VERSION 5.7 ;
  NOWIREEXTENSIONATPIN ON ;
  DIVIDERCHAR "/" ;
  BUSBITCHARS "[]" ;
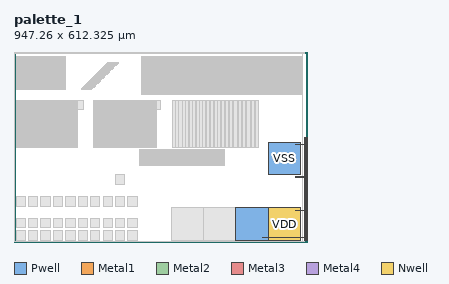
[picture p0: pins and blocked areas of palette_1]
MACRO palette_1
  CLASS BLOCK ;
  FOREIGN palette_1 ;
  ORIGIN 0.000 0.000 ;
  SIZE 947.260 BY 612.325 ;
  PIN VSS
    DIRECTION INOUT ;
    USE GROUND ;
    PORT
      LAYER Pwell ;
        RECT 819.000 218.000 923.000 322.000 ;
        RECT 715.000 6.000 819.000 110.000 ;
      LAYER Metal1 ;
        RECT 906.130 312.895 945.320 313.880 ;
        RECT 802.090 14.115 945.320 15.110 ;
      LAYER Metal2 ;
        RECT 941.425 312.895 945.425 313.885 ;
        RECT 941.425 14.120 945.430 15.110 ;
      LAYER Metal3 ;
        RECT 941.425 312.895 945.425 313.885 ;
        RECT 941.425 14.120 945.430 15.110 ;
      LAYER Metal4 ;
        RECT 941.425 6.015 945.425 336.370 ;
    END
  END VSS
  PIN VDD
    DIRECTION INOUT ;
    USE POWER ;
    PORT
      LAYER Nwell ;
        RECT 819.000 6.000 923.000 110.000 ;
      LAYER Metal1 ;
        RECT 906.135 208.865 940.095 209.850 ;
        RECT 906.375 100.730 939.890 101.710 ;
      LAYER Metal2 ;
        RECT 936.425 208.860 940.425 209.850 ;
        RECT 936.425 100.725 940.425 101.715 ;
      LAYER Metal3 ;
        RECT 936.425 208.860 940.425 209.850 ;
        RECT 936.425 100.725 940.425 101.715 ;
      LAYER Metal4 ;
        RECT 936.425 6.015 940.425 336.370 ;
    END
  END VDD
  OBS
      LAYER Pwell ;
        RECT 507.000 6.000 611.000 110.000 ;
      LAYER Nwell ;
        RECT 611.000 6.000 715.000 110.000 ;
      LAYER Metal1 ;
        RECT 287.000 116.000 317.000 146.000 ;
        RECT 327.000 116.000 357.000 146.000 ;
        RECT 367.000 116.000 397.000 146.000 ;
        RECT 327.000 46.000 357.000 76.000 ;
        RECT 367.000 46.000 397.000 76.000 ;
        RECT 327.000 6.000 357.000 36.000 ;
        RECT 367.000 6.000 397.000 36.000 ;
      LAYER Metal2 ;
        RECT 207.000 116.000 237.000 146.000 ;
        RECT 247.000 116.000 277.000 146.000 ;
        RECT 287.000 116.000 317.000 146.000 ;
        RECT 247.000 46.000 277.000 76.000 ;
        RECT 287.000 46.000 317.000 76.000 ;
        RECT 247.000 6.000 277.000 36.000 ;
        RECT 287.000 6.000 317.000 36.000 ;
      LAYER Metal3 ;
        RECT 255.420 426.000 285.420 456.000 ;
        RECT 286.420 426.000 316.420 456.000 ;
        RECT 317.420 426.000 347.420 456.000 ;
        RECT 348.420 426.000 378.420 456.000 ;
        RECT 379.420 426.000 409.420 456.000 ;
        RECT 410.420 426.000 440.420 456.000 ;
        RECT 441.420 426.000 471.420 456.000 ;
        RECT 127.000 116.000 157.000 146.000 ;
        RECT 167.000 116.000 197.000 146.000 ;
        RECT 207.000 116.000 237.000 146.000 ;
        RECT 167.000 46.000 197.000 76.000 ;
        RECT 207.000 46.000 237.000 76.000 ;
        RECT 167.000 6.000 197.000 36.000 ;
        RECT 207.000 6.000 237.000 36.000 ;
      LAYER Metal4 ;
        RECT 2.550 608.255 935.650 609.265 ;
        RECT 1.520 6.000 2.530 605.275 ;
        RECT 7.000 426.000 37.000 456.000 ;
        RECT 38.000 426.000 68.000 456.000 ;
        RECT 69.000 426.000 99.000 456.000 ;
        RECT 100.000 426.000 130.000 456.000 ;
        RECT 131.000 426.000 161.000 456.000 ;
        RECT 162.000 426.000 192.000 456.000 ;
        RECT 193.000 426.000 223.000 456.000 ;
        RECT 255.420 306.000 256.420 456.000 ;
        RECT 256.800 306.000 257.800 456.000 ;
        RECT 258.180 306.000 259.180 456.000 ;
        RECT 259.560 306.000 260.560 456.000 ;
        RECT 260.940 306.000 261.940 456.000 ;
        RECT 262.330 306.000 263.330 456.000 ;
        RECT 263.720 306.000 264.720 456.000 ;
        RECT 265.110 306.000 266.110 456.000 ;
        RECT 266.500 306.000 267.500 456.000 ;
        RECT 267.900 306.000 268.900 456.000 ;
        RECT 269.300 306.000 270.300 456.000 ;
        RECT 270.700 306.000 271.700 456.000 ;
        RECT 272.100 306.000 273.100 456.000 ;
        RECT 273.510 306.000 274.510 456.000 ;
        RECT 274.920 306.000 275.920 456.000 ;
        RECT 276.330 306.000 277.330 456.000 ;
        RECT 277.740 306.000 278.740 456.000 ;
        RECT 279.160 306.000 280.160 456.000 ;
        RECT 280.580 306.000 281.580 456.000 ;
        RECT 282.000 306.000 283.000 456.000 ;
        RECT 283.420 306.000 284.420 456.000 ;
        RECT 284.850 306.000 285.850 456.000 ;
        RECT 286.280 306.000 287.280 456.000 ;
        RECT 287.710 306.000 288.710 456.000 ;
        RECT 289.140 306.000 290.140 456.000 ;
        RECT 290.580 306.000 291.580 456.000 ;
        RECT 292.020 306.000 293.020 456.000 ;
        RECT 293.460 306.000 294.460 456.000 ;
        RECT 294.900 306.000 295.900 456.000 ;
        RECT 296.350 306.000 297.350 456.000 ;
        RECT 297.800 306.000 298.800 456.000 ;
        RECT 299.250 306.000 300.250 456.000 ;
        RECT 300.700 306.000 301.700 456.000 ;
        RECT 302.160 306.000 303.160 456.000 ;
        RECT 303.620 306.000 304.620 456.000 ;
        RECT 305.080 306.000 306.080 456.000 ;
        RECT 306.540 306.000 307.540 456.000 ;
        RECT 308.010 306.000 309.010 456.000 ;
        RECT 309.480 306.000 310.480 456.000 ;
        RECT 310.950 306.000 311.950 456.000 ;
        RECT 312.420 306.000 313.420 456.000 ;
        RECT 313.900 306.000 314.900 456.000 ;
        RECT 315.380 306.000 316.380 456.000 ;
        RECT 316.860 306.000 317.860 456.000 ;
        RECT 318.340 306.000 319.340 456.000 ;
        RECT 319.830 306.000 320.830 456.000 ;
        RECT 321.320 306.000 322.320 456.000 ;
        RECT 322.810 306.000 323.810 456.000 ;
        RECT 324.300 306.000 325.300 456.000 ;
        RECT 325.800 306.000 326.800 456.000 ;
        RECT 327.300 306.000 328.300 456.000 ;
        RECT 328.800 306.000 329.800 456.000 ;
        RECT 330.300 306.000 331.300 456.000 ;
        RECT 331.810 306.000 332.810 456.000 ;
        RECT 333.320 306.000 334.320 456.000 ;
        RECT 334.830 306.000 335.830 456.000 ;
        RECT 336.340 306.000 337.340 456.000 ;
        RECT 337.860 306.000 338.860 456.000 ;
        RECT 339.380 306.000 340.380 456.000 ;
        RECT 340.900 306.000 341.900 456.000 ;
        RECT 342.420 306.000 343.420 456.000 ;
        RECT 343.950 306.000 344.950 456.000 ;
        RECT 345.480 306.000 346.480 456.000 ;
        RECT 347.010 306.000 348.010 456.000 ;
        RECT 348.540 306.000 349.540 456.000 ;
        RECT 350.080 306.000 351.080 456.000 ;
        RECT 351.620 306.000 352.620 456.000 ;
        RECT 353.160 306.000 354.160 456.000 ;
        RECT 354.700 306.000 355.700 456.000 ;
        RECT 356.250 306.000 357.250 456.000 ;
        RECT 357.800 306.000 358.800 456.000 ;
        RECT 359.350 306.000 360.350 456.000 ;
        RECT 360.900 306.000 361.900 456.000 ;
        RECT 362.460 306.000 363.460 456.000 ;
        RECT 364.020 306.000 365.020 456.000 ;
        RECT 365.580 306.000 366.580 456.000 ;
        RECT 367.140 306.000 368.140 456.000 ;
        RECT 368.710 306.000 369.710 456.000 ;
        RECT 370.280 306.000 371.280 456.000 ;
        RECT 371.850 306.000 372.850 456.000 ;
        RECT 373.420 306.000 374.420 456.000 ;
        RECT 375.000 306.000 376.000 456.000 ;
        RECT 376.580 306.000 377.580 456.000 ;
        RECT 378.160 306.000 379.160 456.000 ;
        RECT 379.740 306.000 380.740 456.000 ;
        RECT 381.330 306.000 382.330 456.000 ;
        RECT 382.920 306.000 383.920 456.000 ;
        RECT 384.510 306.000 385.510 456.000 ;
        RECT 386.100 306.000 387.100 456.000 ;
        RECT 387.700 306.000 388.700 456.000 ;
        RECT 389.300 306.000 390.300 456.000 ;
        RECT 390.900 306.000 391.900 456.000 ;
        RECT 392.500 306.000 393.500 456.000 ;
        RECT 394.110 306.000 395.110 456.000 ;
        RECT 395.720 306.000 396.720 456.000 ;
        RECT 397.330 306.000 398.330 456.000 ;
        RECT 398.940 306.000 399.940 456.000 ;
        RECT 400.560 306.000 401.560 456.000 ;
        RECT 402.180 306.000 403.180 456.000 ;
        RECT 403.800 306.000 404.800 456.000 ;
        RECT 405.420 306.000 406.420 456.000 ;
        RECT 407.050 306.000 408.050 456.000 ;
        RECT 408.680 306.000 409.680 456.000 ;
        RECT 410.310 306.000 411.310 456.000 ;
        RECT 411.940 306.000 412.940 456.000 ;
        RECT 413.580 306.000 414.580 456.000 ;
        RECT 415.220 306.000 416.220 456.000 ;
        RECT 416.860 306.000 417.860 456.000 ;
        RECT 418.500 306.000 419.500 456.000 ;
        RECT 420.150 306.000 421.150 456.000 ;
        RECT 421.800 306.000 422.800 456.000 ;
        RECT 423.450 306.000 424.450 456.000 ;
        RECT 425.100 306.000 426.100 456.000 ;
        RECT 426.760 306.000 427.760 456.000 ;
        RECT 428.420 306.000 429.420 456.000 ;
        RECT 430.080 306.000 431.080 456.000 ;
        RECT 431.740 306.000 432.740 456.000 ;
        RECT 433.410 306.000 434.410 456.000 ;
        RECT 435.080 306.000 436.080 456.000 ;
        RECT 436.750 306.000 437.750 456.000 ;
        RECT 438.420 306.000 439.420 456.000 ;
        RECT 440.100 306.000 441.100 456.000 ;
        RECT 441.780 306.000 442.780 456.000 ;
        RECT 443.460 306.000 444.460 456.000 ;
        RECT 445.140 306.000 446.140 456.000 ;
        RECT 446.830 306.000 447.830 456.000 ;
        RECT 448.520 306.000 449.520 456.000 ;
        RECT 450.210 306.000 451.210 456.000 ;
        RECT 451.900 306.000 452.900 456.000 ;
        RECT 453.600 306.000 454.600 456.000 ;
        RECT 455.300 306.000 456.300 456.000 ;
        RECT 457.000 306.000 458.000 456.000 ;
        RECT 458.700 306.000 459.700 456.000 ;
        RECT 326.400 216.000 357.600 216.600 ;
        RECT 326.400 186.000 327.000 216.000 ;
        RECT 357.000 186.000 357.600 216.000 ;
        RECT 326.400 185.400 357.600 186.000 ;
        RECT 47.000 116.000 77.000 146.000 ;
        RECT 87.000 116.000 117.000 146.000 ;
        RECT 127.000 116.000 157.000 146.000 ;
        RECT 87.000 46.000 117.000 76.000 ;
        RECT 127.000 46.000 157.000 76.000 ;
        RECT 87.000 6.000 117.000 36.000 ;
        RECT 127.000 6.000 157.000 36.000 ;
        RECT 928.680 6.000 929.130 605.275 ;
        RECT 1.870 0.785 934.970 1.795 ;
      LAYER Metal5 ;
        RECT 2.550 608.255 935.650 609.265 ;
        RECT 1.520 6.000 2.530 605.275 ;
        RECT 9.265 596.390 166.265 597.390 ;
        RECT 9.265 594.390 166.265 595.390 ;
        RECT 9.265 592.390 166.265 593.390 ;
        RECT 9.265 590.390 166.265 591.390 ;
        RECT 9.265 588.390 166.265 589.390 ;
        RECT 9.265 586.390 166.265 587.390 ;
        RECT 9.265 584.390 166.265 585.390 ;
        RECT 9.265 582.390 166.265 583.390 ;
        RECT 9.265 580.390 166.265 581.390 ;
        RECT 9.265 578.390 166.265 579.390 ;
        RECT 303.265 578.390 305.265 579.390 ;
        RECT 302.265 577.390 304.265 578.390 ;
        RECT 307.265 578.385 309.265 579.385 ;
        RECT 9.265 576.390 166.265 577.390 ;
        RECT 301.265 576.390 303.265 577.390 ;
        RECT 306.265 577.385 308.265 578.385 ;
        RECT 311.265 578.380 313.265 579.380 ;
        RECT 315.265 578.380 317.265 579.380 ;
        RECT 319.265 578.380 321.265 579.380 ;
        RECT 323.265 578.380 325.265 579.380 ;
        RECT 327.265 578.380 329.265 579.380 ;
        RECT 331.265 578.380 333.265 579.380 ;
        RECT 335.265 578.380 337.265 579.380 ;
        RECT 300.265 575.390 302.265 576.390 ;
        RECT 305.265 576.385 307.265 577.385 ;
        RECT 310.265 577.380 312.265 578.380 ;
        RECT 314.265 577.380 316.265 578.380 ;
        RECT 318.265 577.380 320.265 578.380 ;
        RECT 322.265 577.380 324.265 578.380 ;
        RECT 326.265 577.380 328.265 578.380 ;
        RECT 330.265 577.380 332.265 578.380 ;
        RECT 334.265 577.380 336.265 578.380 ;
        RECT 9.265 574.390 166.265 575.390 ;
        RECT 299.265 574.390 301.265 575.390 ;
        RECT 304.265 575.385 306.265 576.385 ;
        RECT 309.265 576.380 311.265 577.380 ;
        RECT 313.265 576.380 315.265 577.380 ;
        RECT 317.265 576.380 319.265 577.380 ;
        RECT 321.265 576.380 323.265 577.380 ;
        RECT 325.265 576.380 327.265 577.380 ;
        RECT 329.265 576.380 331.265 577.380 ;
        RECT 333.265 576.380 335.265 577.380 ;
        RECT 298.265 573.390 300.265 574.390 ;
        RECT 303.265 574.385 305.265 575.385 ;
        RECT 308.265 575.380 310.265 576.380 ;
        RECT 312.265 575.380 314.265 576.380 ;
        RECT 316.265 575.380 318.265 576.380 ;
        RECT 320.265 575.380 322.265 576.380 ;
        RECT 324.265 575.380 326.265 576.380 ;
        RECT 328.265 575.380 330.265 576.380 ;
        RECT 332.265 575.380 334.265 576.380 ;
        RECT 9.265 572.390 166.265 573.390 ;
        RECT 297.265 572.390 299.265 573.390 ;
        RECT 302.265 573.385 304.265 574.385 ;
        RECT 307.265 574.380 309.265 575.380 ;
        RECT 311.265 574.380 313.265 575.380 ;
        RECT 315.265 574.380 317.265 575.380 ;
        RECT 319.265 574.380 321.265 575.380 ;
        RECT 323.265 574.380 325.265 575.380 ;
        RECT 327.265 574.380 329.265 575.380 ;
        RECT 331.265 574.380 333.265 575.380 ;
        RECT 296.265 571.390 298.265 572.390 ;
        RECT 301.265 572.385 303.265 573.385 ;
        RECT 306.265 573.380 308.265 574.380 ;
        RECT 310.265 573.380 312.265 574.380 ;
        RECT 314.265 573.380 316.265 574.380 ;
        RECT 318.265 573.380 320.265 574.380 ;
        RECT 322.265 573.380 324.265 574.380 ;
        RECT 326.265 573.380 328.265 574.380 ;
        RECT 330.265 573.380 332.265 574.380 ;
        RECT 9.265 570.390 166.265 571.390 ;
        RECT 295.265 570.390 297.265 571.390 ;
        RECT 300.265 571.385 302.265 572.385 ;
        RECT 305.265 572.380 307.265 573.380 ;
        RECT 309.265 572.380 311.265 573.380 ;
        RECT 313.265 572.380 315.265 573.380 ;
        RECT 317.265 572.380 319.265 573.380 ;
        RECT 321.265 572.380 323.265 573.380 ;
        RECT 325.265 572.380 327.265 573.380 ;
        RECT 329.265 572.380 331.265 573.380 ;
        RECT 294.265 569.390 296.265 570.390 ;
        RECT 299.265 570.385 301.265 571.385 ;
        RECT 304.265 571.380 306.265 572.380 ;
        RECT 308.265 571.380 310.265 572.380 ;
        RECT 312.265 571.380 314.265 572.380 ;
        RECT 316.265 571.380 318.265 572.380 ;
        RECT 320.265 571.380 322.265 572.380 ;
        RECT 324.265 571.380 326.265 572.380 ;
        RECT 328.265 571.380 330.265 572.380 ;
        RECT 9.265 568.390 166.265 569.390 ;
        RECT 293.265 568.390 295.265 569.390 ;
        RECT 298.265 569.385 300.265 570.385 ;
        RECT 303.265 570.380 305.265 571.380 ;
        RECT 307.265 570.380 309.265 571.380 ;
        RECT 311.265 570.380 313.265 571.380 ;
        RECT 315.265 570.380 317.265 571.380 ;
        RECT 319.265 570.380 321.265 571.380 ;
        RECT 323.265 570.380 325.265 571.380 ;
        RECT 327.265 570.380 329.265 571.380 ;
        RECT 292.265 567.390 294.265 568.390 ;
        RECT 297.265 568.385 299.265 569.385 ;
        RECT 302.265 569.380 304.265 570.380 ;
        RECT 306.265 569.380 308.265 570.380 ;
        RECT 310.265 569.380 312.265 570.380 ;
        RECT 314.265 569.380 316.265 570.380 ;
        RECT 318.265 569.380 320.265 570.380 ;
        RECT 322.265 569.380 324.265 570.380 ;
        RECT 326.265 569.380 328.265 570.380 ;
        RECT 9.265 566.390 166.265 567.390 ;
        RECT 291.265 566.390 293.265 567.390 ;
        RECT 296.265 567.385 298.265 568.385 ;
        RECT 301.265 568.380 303.265 569.380 ;
        RECT 305.265 568.380 307.265 569.380 ;
        RECT 309.265 568.380 311.265 569.380 ;
        RECT 313.265 568.380 315.265 569.380 ;
        RECT 317.265 568.380 319.265 569.380 ;
        RECT 321.265 568.380 323.265 569.380 ;
        RECT 325.265 568.380 327.265 569.380 ;
        RECT 290.265 565.390 292.265 566.390 ;
        RECT 295.265 566.385 297.265 567.385 ;
        RECT 300.265 567.380 302.265 568.380 ;
        RECT 304.265 567.380 306.265 568.380 ;
        RECT 308.265 567.380 310.265 568.380 ;
        RECT 312.265 567.380 314.265 568.380 ;
        RECT 316.265 567.380 318.265 568.380 ;
        RECT 320.265 567.380 322.265 568.380 ;
        RECT 324.265 567.380 326.265 568.380 ;
        RECT 9.265 564.390 166.265 565.390 ;
        RECT 289.265 564.390 291.265 565.390 ;
        RECT 294.265 565.385 296.265 566.385 ;
        RECT 299.265 566.380 301.265 567.380 ;
        RECT 303.265 566.380 305.265 567.380 ;
        RECT 307.265 566.380 309.265 567.380 ;
        RECT 311.265 566.380 313.265 567.380 ;
        RECT 315.265 566.380 317.265 567.380 ;
        RECT 319.265 566.380 321.265 567.380 ;
        RECT 323.265 566.380 325.265 567.380 ;
        RECT 288.265 563.390 290.265 564.390 ;
        RECT 293.265 564.385 295.265 565.385 ;
        RECT 298.265 565.380 300.265 566.380 ;
        RECT 302.265 565.380 304.265 566.380 ;
        RECT 306.265 565.380 308.265 566.380 ;
        RECT 310.265 565.380 312.265 566.380 ;
        RECT 314.265 565.380 316.265 566.380 ;
        RECT 318.265 565.380 320.265 566.380 ;
        RECT 322.265 565.380 324.265 566.380 ;
        RECT 9.265 562.390 166.265 563.390 ;
        RECT 287.265 562.390 289.265 563.390 ;
        RECT 292.265 563.385 294.265 564.385 ;
        RECT 297.265 564.380 299.265 565.380 ;
        RECT 301.265 564.380 303.265 565.380 ;
        RECT 305.265 564.380 307.265 565.380 ;
        RECT 309.265 564.380 311.265 565.380 ;
        RECT 313.265 564.380 315.265 565.380 ;
        RECT 317.265 564.380 319.265 565.380 ;
        RECT 321.265 564.380 323.265 565.380 ;
        RECT 286.265 561.390 288.265 562.390 ;
        RECT 291.265 562.385 293.265 563.385 ;
        RECT 296.265 563.380 298.265 564.380 ;
        RECT 300.265 563.380 302.265 564.380 ;
        RECT 304.265 563.380 306.265 564.380 ;
        RECT 308.265 563.380 310.265 564.380 ;
        RECT 312.265 563.380 314.265 564.380 ;
        RECT 316.265 563.380 318.265 564.380 ;
        RECT 320.265 563.380 322.265 564.380 ;
        RECT 9.265 560.390 166.265 561.390 ;
        RECT 285.265 560.390 287.265 561.390 ;
        RECT 290.265 561.385 292.265 562.385 ;
        RECT 295.265 562.380 297.265 563.380 ;
        RECT 299.265 562.380 301.265 563.380 ;
        RECT 303.265 562.380 305.265 563.380 ;
        RECT 307.265 562.380 309.265 563.380 ;
        RECT 311.265 562.380 313.265 563.380 ;
        RECT 315.265 562.380 317.265 563.380 ;
        RECT 319.265 562.380 321.265 563.380 ;
        RECT 284.265 559.390 286.265 560.390 ;
        RECT 289.265 560.385 291.265 561.385 ;
        RECT 294.265 561.380 296.265 562.380 ;
        RECT 298.265 561.380 300.265 562.380 ;
        RECT 302.265 561.380 304.265 562.380 ;
        RECT 306.265 561.380 308.265 562.380 ;
        RECT 310.265 561.380 312.265 562.380 ;
        RECT 314.265 561.380 316.265 562.380 ;
        RECT 318.265 561.380 320.265 562.380 ;
        RECT 9.265 558.390 166.265 559.390 ;
        RECT 283.265 558.390 285.265 559.390 ;
        RECT 288.265 559.385 290.265 560.385 ;
        RECT 293.265 560.380 295.265 561.380 ;
        RECT 297.265 560.380 299.265 561.380 ;
        RECT 301.265 560.380 303.265 561.380 ;
        RECT 305.265 560.380 307.265 561.380 ;
        RECT 309.265 560.380 311.265 561.380 ;
        RECT 313.265 560.380 315.265 561.380 ;
        RECT 317.265 560.380 319.265 561.380 ;
        RECT 282.265 557.390 284.265 558.390 ;
        RECT 287.265 558.385 289.265 559.385 ;
        RECT 292.265 559.380 294.265 560.380 ;
        RECT 296.265 559.380 298.265 560.380 ;
        RECT 300.265 559.380 302.265 560.380 ;
        RECT 304.265 559.380 306.265 560.380 ;
        RECT 308.265 559.380 310.265 560.380 ;
        RECT 312.265 559.380 314.265 560.380 ;
        RECT 316.265 559.380 318.265 560.380 ;
        RECT 9.265 556.390 166.265 557.390 ;
        RECT 281.265 556.390 283.265 557.390 ;
        RECT 286.265 557.385 288.265 558.385 ;
        RECT 291.265 558.380 293.265 559.380 ;
        RECT 295.265 558.380 297.265 559.380 ;
        RECT 299.265 558.380 301.265 559.380 ;
        RECT 303.265 558.380 305.265 559.380 ;
        RECT 307.265 558.380 309.265 559.380 ;
        RECT 311.265 558.380 313.265 559.380 ;
        RECT 315.265 558.380 317.265 559.380 ;
        RECT 280.265 555.390 282.265 556.390 ;
        RECT 285.265 556.385 287.265 557.385 ;
        RECT 290.265 557.380 292.265 558.380 ;
        RECT 294.265 557.380 296.265 558.380 ;
        RECT 298.265 557.380 300.265 558.380 ;
        RECT 302.265 557.380 304.265 558.380 ;
        RECT 306.265 557.380 308.265 558.380 ;
        RECT 310.265 557.380 312.265 558.380 ;
        RECT 314.265 557.380 316.265 558.380 ;
        RECT 9.265 554.390 166.265 555.390 ;
        RECT 279.265 554.390 281.265 555.390 ;
        RECT 284.265 555.385 286.265 556.385 ;
        RECT 289.265 556.380 291.265 557.380 ;
        RECT 293.265 556.380 295.265 557.380 ;
        RECT 297.265 556.380 299.265 557.380 ;
        RECT 301.265 556.380 303.265 557.380 ;
        RECT 305.265 556.380 307.265 557.380 ;
        RECT 309.265 556.380 311.265 557.380 ;
        RECT 313.265 556.380 315.265 557.380 ;
        RECT 278.265 553.390 280.265 554.390 ;
        RECT 283.265 554.385 285.265 555.385 ;
        RECT 288.265 555.380 290.265 556.380 ;
        RECT 292.265 555.380 294.265 556.380 ;
        RECT 296.265 555.380 298.265 556.380 ;
        RECT 300.265 555.380 302.265 556.380 ;
        RECT 304.265 555.380 306.265 556.380 ;
        RECT 308.265 555.380 310.265 556.380 ;
        RECT 312.265 555.380 314.265 556.380 ;
        RECT 9.265 552.390 166.265 553.390 ;
        RECT 277.265 552.390 279.265 553.390 ;
        RECT 282.265 553.385 284.265 554.385 ;
        RECT 287.265 554.380 289.265 555.380 ;
        RECT 291.265 554.380 293.265 555.380 ;
        RECT 295.265 554.380 297.265 555.380 ;
        RECT 299.265 554.380 301.265 555.380 ;
        RECT 303.265 554.380 305.265 555.380 ;
        RECT 307.265 554.380 309.265 555.380 ;
        RECT 311.265 554.380 313.265 555.380 ;
        RECT 276.265 551.390 278.265 552.390 ;
        RECT 281.265 552.385 283.265 553.385 ;
        RECT 286.265 553.380 288.265 554.380 ;
        RECT 290.265 553.380 292.265 554.380 ;
        RECT 294.265 553.380 296.265 554.380 ;
        RECT 298.265 553.380 300.265 554.380 ;
        RECT 302.265 553.380 304.265 554.380 ;
        RECT 306.265 553.380 308.265 554.380 ;
        RECT 310.265 553.380 312.265 554.380 ;
        RECT 9.265 550.390 166.265 551.390 ;
        RECT 275.265 550.390 277.265 551.390 ;
        RECT 280.265 551.385 282.265 552.385 ;
        RECT 285.265 552.380 287.265 553.380 ;
        RECT 289.265 552.380 291.265 553.380 ;
        RECT 293.265 552.380 295.265 553.380 ;
        RECT 297.265 552.380 299.265 553.380 ;
        RECT 301.265 552.380 303.265 553.380 ;
        RECT 305.265 552.380 307.265 553.380 ;
        RECT 309.265 552.380 311.265 553.380 ;
        RECT 274.265 549.390 276.265 550.390 ;
        RECT 279.265 550.385 281.265 551.385 ;
        RECT 284.265 551.380 286.265 552.380 ;
        RECT 288.265 551.380 290.265 552.380 ;
        RECT 292.265 551.380 294.265 552.380 ;
        RECT 296.265 551.380 298.265 552.380 ;
        RECT 300.265 551.380 302.265 552.380 ;
        RECT 304.265 551.380 306.265 552.380 ;
        RECT 308.265 551.380 310.265 552.380 ;
        RECT 9.265 548.390 166.265 549.390 ;
        RECT 273.265 548.390 275.265 549.390 ;
        RECT 278.265 549.385 280.265 550.385 ;
        RECT 283.265 550.380 285.265 551.380 ;
        RECT 287.265 550.380 289.265 551.380 ;
        RECT 291.265 550.380 293.265 551.380 ;
        RECT 295.265 550.380 297.265 551.380 ;
        RECT 299.265 550.380 301.265 551.380 ;
        RECT 303.265 550.380 305.265 551.380 ;
        RECT 307.265 550.380 309.265 551.380 ;
        RECT 272.265 547.390 274.265 548.390 ;
        RECT 277.265 548.385 279.265 549.385 ;
        RECT 282.265 549.380 284.265 550.380 ;
        RECT 286.265 549.380 288.265 550.380 ;
        RECT 290.265 549.380 292.265 550.380 ;
        RECT 294.265 549.380 296.265 550.380 ;
        RECT 298.265 549.380 300.265 550.380 ;
        RECT 302.265 549.380 304.265 550.380 ;
        RECT 306.265 549.380 308.265 550.380 ;
        RECT 9.265 546.390 166.265 547.390 ;
        RECT 271.265 546.390 273.265 547.390 ;
        RECT 276.265 547.385 278.265 548.385 ;
        RECT 281.265 548.380 283.265 549.380 ;
        RECT 285.265 548.380 287.265 549.380 ;
        RECT 289.265 548.380 291.265 549.380 ;
        RECT 293.265 548.380 295.265 549.380 ;
        RECT 297.265 548.380 299.265 549.380 ;
        RECT 301.265 548.380 303.265 549.380 ;
        RECT 305.265 548.380 307.265 549.380 ;
        RECT 270.265 545.390 272.265 546.390 ;
        RECT 275.265 546.385 277.265 547.385 ;
        RECT 280.265 547.380 282.265 548.380 ;
        RECT 284.265 547.380 286.265 548.380 ;
        RECT 288.265 547.380 290.265 548.380 ;
        RECT 292.265 547.380 294.265 548.380 ;
        RECT 296.265 547.380 298.265 548.380 ;
        RECT 300.265 547.380 302.265 548.380 ;
        RECT 304.265 547.380 306.265 548.380 ;
        RECT 9.265 544.390 166.265 545.390 ;
        RECT 269.265 544.390 271.265 545.390 ;
        RECT 274.265 545.385 276.265 546.385 ;
        RECT 279.265 546.380 281.265 547.380 ;
        RECT 283.265 546.380 285.265 547.380 ;
        RECT 287.265 546.380 289.265 547.380 ;
        RECT 291.265 546.380 293.265 547.380 ;
        RECT 295.265 546.380 297.265 547.380 ;
        RECT 299.265 546.380 301.265 547.380 ;
        RECT 303.265 546.380 305.265 547.380 ;
        RECT 268.265 543.390 270.265 544.390 ;
        RECT 273.265 544.385 275.265 545.385 ;
        RECT 278.265 545.380 280.265 546.380 ;
        RECT 282.265 545.380 284.265 546.380 ;
        RECT 286.265 545.380 288.265 546.380 ;
        RECT 290.265 545.380 292.265 546.380 ;
        RECT 294.265 545.380 296.265 546.380 ;
        RECT 298.265 545.380 300.265 546.380 ;
        RECT 302.265 545.380 304.265 546.380 ;
        RECT 9.265 542.390 166.265 543.390 ;
        RECT 267.265 542.390 269.265 543.390 ;
        RECT 272.265 543.385 274.265 544.385 ;
        RECT 277.265 544.380 279.265 545.380 ;
        RECT 281.265 544.380 283.265 545.380 ;
        RECT 285.265 544.380 287.265 545.380 ;
        RECT 289.265 544.380 291.265 545.380 ;
        RECT 293.265 544.380 295.265 545.380 ;
        RECT 297.265 544.380 299.265 545.380 ;
        RECT 301.265 544.380 303.265 545.380 ;
        RECT 266.265 541.390 268.265 542.390 ;
        RECT 271.265 542.385 273.265 543.385 ;
        RECT 276.265 543.380 278.265 544.380 ;
        RECT 280.265 543.380 282.265 544.380 ;
        RECT 284.265 543.380 286.265 544.380 ;
        RECT 288.265 543.380 290.265 544.380 ;
        RECT 292.265 543.380 294.265 544.380 ;
        RECT 296.265 543.380 298.265 544.380 ;
        RECT 300.265 543.380 302.265 544.380 ;
        RECT 9.265 540.390 166.265 541.390 ;
        RECT 265.265 540.390 267.265 541.390 ;
        RECT 270.265 541.385 272.265 542.385 ;
        RECT 275.265 542.380 277.265 543.380 ;
        RECT 279.265 542.380 281.265 543.380 ;
        RECT 283.265 542.380 285.265 543.380 ;
        RECT 287.265 542.380 289.265 543.380 ;
        RECT 291.265 542.380 293.265 543.380 ;
        RECT 295.265 542.380 297.265 543.380 ;
        RECT 299.265 542.380 301.265 543.380 ;
        RECT 9.265 490.390 10.265 540.390 ;
        RECT 11.265 490.390 12.265 540.390 ;
        RECT 13.265 490.390 14.265 540.390 ;
        RECT 15.265 490.390 16.265 540.390 ;
        RECT 17.265 490.390 18.265 540.390 ;
        RECT 19.265 490.390 20.265 540.390 ;
        RECT 21.265 490.390 22.265 540.390 ;
        RECT 23.265 490.390 24.265 540.390 ;
        RECT 25.265 490.390 26.265 540.390 ;
        RECT 27.265 490.390 28.265 540.390 ;
        RECT 29.265 490.390 30.265 540.390 ;
        RECT 31.265 490.390 32.265 540.390 ;
        RECT 33.265 490.390 34.265 540.390 ;
        RECT 35.265 490.390 36.265 540.390 ;
        RECT 37.265 490.390 38.265 540.390 ;
        RECT 39.265 490.390 40.265 540.390 ;
        RECT 41.265 490.390 42.265 540.390 ;
        RECT 43.265 490.390 44.265 540.390 ;
        RECT 45.265 490.390 46.265 540.390 ;
        RECT 47.265 490.390 48.265 540.390 ;
        RECT 49.265 490.390 50.265 540.390 ;
        RECT 51.265 490.390 52.265 540.390 ;
        RECT 53.265 490.390 54.265 540.390 ;
        RECT 55.265 490.390 56.265 540.390 ;
        RECT 57.265 490.390 58.265 540.390 ;
        RECT 59.265 490.390 60.265 540.390 ;
        RECT 61.265 490.390 62.265 540.390 ;
        RECT 63.265 490.390 64.265 540.390 ;
        RECT 65.265 490.390 66.265 540.390 ;
        RECT 67.265 490.390 68.265 540.390 ;
        RECT 69.265 490.390 70.265 540.390 ;
        RECT 71.265 490.390 72.265 540.390 ;
        RECT 73.265 490.390 74.265 540.390 ;
        RECT 75.265 490.390 76.265 540.390 ;
        RECT 77.265 490.390 78.265 540.390 ;
        RECT 79.265 490.390 80.265 540.390 ;
        RECT 81.265 490.390 82.265 540.390 ;
        RECT 83.265 490.390 84.265 540.390 ;
        RECT 85.265 490.390 86.265 540.390 ;
        RECT 87.265 490.390 88.265 540.390 ;
        RECT 89.265 490.390 90.265 540.390 ;
        RECT 91.265 490.390 92.265 540.390 ;
        RECT 93.265 490.390 94.265 540.390 ;
        RECT 95.265 490.390 96.265 540.390 ;
        RECT 97.265 490.390 98.265 540.390 ;
        RECT 99.265 490.390 100.265 540.390 ;
        RECT 101.265 490.390 102.265 540.390 ;
        RECT 103.265 490.390 104.265 540.390 ;
        RECT 105.265 490.390 106.265 540.390 ;
        RECT 107.265 490.390 108.265 540.390 ;
        RECT 109.265 490.390 110.265 540.390 ;
        RECT 111.265 490.390 112.265 540.390 ;
        RECT 113.265 490.390 114.265 540.390 ;
        RECT 115.265 490.390 116.265 540.390 ;
        RECT 117.265 490.390 118.265 540.390 ;
        RECT 119.265 490.390 120.265 540.390 ;
        RECT 121.265 490.390 122.265 540.390 ;
        RECT 123.265 490.390 124.265 540.390 ;
        RECT 125.265 490.390 126.265 540.390 ;
        RECT 127.265 490.390 128.265 540.390 ;
        RECT 129.265 490.390 130.265 540.390 ;
        RECT 131.265 490.390 132.265 540.390 ;
        RECT 133.265 490.390 134.265 540.390 ;
        RECT 135.265 490.390 136.265 540.390 ;
        RECT 137.265 490.390 138.265 540.390 ;
        RECT 139.265 490.390 140.265 540.390 ;
        RECT 141.265 490.390 142.265 540.390 ;
        RECT 143.265 490.390 144.265 540.390 ;
        RECT 145.265 490.390 146.265 540.390 ;
        RECT 147.265 490.390 148.265 540.390 ;
        RECT 149.265 490.390 150.265 540.390 ;
        RECT 151.265 490.390 152.265 540.390 ;
        RECT 153.265 490.390 154.265 540.390 ;
        RECT 155.265 490.390 156.265 540.390 ;
        RECT 157.265 490.390 158.265 540.390 ;
        RECT 159.265 490.390 160.265 540.390 ;
        RECT 161.265 490.390 162.265 540.390 ;
        RECT 163.265 490.390 164.265 540.390 ;
        RECT 165.265 490.390 166.265 540.390 ;
        RECT 264.265 539.390 266.265 540.390 ;
        RECT 269.265 540.385 271.265 541.385 ;
        RECT 274.265 541.380 276.265 542.380 ;
        RECT 278.265 541.380 280.265 542.380 ;
        RECT 282.265 541.380 284.265 542.380 ;
        RECT 286.265 541.380 288.265 542.380 ;
        RECT 290.265 541.380 292.265 542.380 ;
        RECT 294.265 541.380 296.265 542.380 ;
        RECT 298.265 541.380 300.265 542.380 ;
        RECT 263.265 538.390 265.265 539.390 ;
        RECT 268.265 539.385 270.265 540.385 ;
        RECT 273.265 540.380 275.265 541.380 ;
        RECT 277.265 540.380 279.265 541.380 ;
        RECT 281.265 540.380 283.265 541.380 ;
        RECT 285.265 540.380 287.265 541.380 ;
        RECT 289.265 540.380 291.265 541.380 ;
        RECT 293.265 540.380 295.265 541.380 ;
        RECT 297.265 540.380 299.265 541.380 ;
        RECT 262.265 537.390 264.265 538.390 ;
        RECT 267.265 538.385 269.265 539.385 ;
        RECT 272.265 539.380 274.265 540.380 ;
        RECT 276.265 539.380 278.265 540.380 ;
        RECT 280.265 539.380 282.265 540.380 ;
        RECT 284.265 539.380 286.265 540.380 ;
        RECT 288.265 539.380 290.265 540.380 ;
        RECT 292.265 539.380 294.265 540.380 ;
        RECT 296.265 539.380 298.265 540.380 ;
        RECT 261.265 536.390 263.265 537.390 ;
        RECT 266.265 537.385 268.265 538.385 ;
        RECT 271.265 538.380 273.265 539.380 ;
        RECT 275.265 538.380 277.265 539.380 ;
        RECT 279.265 538.380 281.265 539.380 ;
        RECT 283.265 538.380 285.265 539.380 ;
        RECT 287.265 538.380 289.265 539.380 ;
        RECT 291.265 538.380 293.265 539.380 ;
        RECT 295.265 538.380 297.265 539.380 ;
        RECT 260.265 535.390 262.265 536.390 ;
        RECT 265.265 536.385 267.265 537.385 ;
        RECT 270.265 537.380 272.265 538.380 ;
        RECT 274.265 537.380 276.265 538.380 ;
        RECT 278.265 537.380 280.265 538.380 ;
        RECT 282.265 537.380 284.265 538.380 ;
        RECT 286.265 537.380 288.265 538.380 ;
        RECT 290.265 537.380 292.265 538.380 ;
        RECT 294.265 537.380 296.265 538.380 ;
        RECT 259.265 534.390 261.265 535.390 ;
        RECT 264.265 535.385 266.265 536.385 ;
        RECT 269.265 536.380 271.265 537.380 ;
        RECT 273.265 536.380 275.265 537.380 ;
        RECT 277.265 536.380 279.265 537.380 ;
        RECT 281.265 536.380 283.265 537.380 ;
        RECT 285.265 536.380 287.265 537.380 ;
        RECT 289.265 536.380 291.265 537.380 ;
        RECT 293.265 536.380 295.265 537.380 ;
        RECT 258.265 533.390 260.265 534.390 ;
        RECT 263.265 534.385 265.265 535.385 ;
        RECT 268.265 535.380 270.265 536.380 ;
        RECT 272.265 535.380 274.265 536.380 ;
        RECT 276.265 535.380 278.265 536.380 ;
        RECT 280.265 535.380 282.265 536.380 ;
        RECT 284.265 535.380 286.265 536.380 ;
        RECT 288.265 535.380 290.265 536.380 ;
        RECT 292.265 535.380 294.265 536.380 ;
        RECT 257.265 532.390 259.265 533.390 ;
        RECT 262.265 533.385 264.265 534.385 ;
        RECT 267.265 534.380 269.265 535.380 ;
        RECT 271.265 534.380 273.265 535.380 ;
        RECT 275.265 534.380 277.265 535.380 ;
        RECT 279.265 534.380 281.265 535.380 ;
        RECT 283.265 534.380 285.265 535.380 ;
        RECT 287.265 534.380 289.265 535.380 ;
        RECT 291.265 534.380 293.265 535.380 ;
        RECT 256.265 531.390 258.265 532.390 ;
        RECT 261.265 532.385 263.265 533.385 ;
        RECT 266.265 533.380 268.265 534.380 ;
        RECT 270.265 533.380 272.265 534.380 ;
        RECT 274.265 533.380 276.265 534.380 ;
        RECT 278.265 533.380 280.265 534.380 ;
        RECT 282.265 533.380 284.265 534.380 ;
        RECT 286.265 533.380 288.265 534.380 ;
        RECT 290.265 533.380 292.265 534.380 ;
        RECT 255.265 530.390 257.265 531.390 ;
        RECT 260.265 531.385 262.265 532.385 ;
        RECT 265.265 532.380 267.265 533.380 ;
        RECT 269.265 532.380 271.265 533.380 ;
        RECT 273.265 532.380 275.265 533.380 ;
        RECT 277.265 532.380 279.265 533.380 ;
        RECT 281.265 532.380 283.265 533.380 ;
        RECT 285.265 532.380 287.265 533.380 ;
        RECT 289.265 532.380 291.265 533.380 ;
        RECT 254.265 529.390 256.265 530.390 ;
        RECT 259.265 530.385 261.265 531.385 ;
        RECT 264.265 531.380 266.265 532.380 ;
        RECT 268.265 531.380 270.265 532.380 ;
        RECT 272.265 531.380 274.265 532.380 ;
        RECT 276.265 531.380 278.265 532.380 ;
        RECT 280.265 531.380 282.265 532.380 ;
        RECT 284.265 531.380 286.265 532.380 ;
        RECT 288.265 531.380 290.265 532.380 ;
        RECT 253.265 528.390 255.265 529.390 ;
        RECT 258.265 529.385 260.265 530.385 ;
        RECT 263.265 530.380 265.265 531.380 ;
        RECT 267.265 530.380 269.265 531.380 ;
        RECT 271.265 530.380 273.265 531.380 ;
        RECT 275.265 530.380 277.265 531.380 ;
        RECT 279.265 530.380 281.265 531.380 ;
        RECT 283.265 530.380 285.265 531.380 ;
        RECT 287.265 530.380 289.265 531.380 ;
        RECT 252.265 527.390 254.265 528.390 ;
        RECT 257.265 528.385 259.265 529.385 ;
        RECT 262.265 529.380 264.265 530.380 ;
        RECT 266.265 529.380 268.265 530.380 ;
        RECT 270.265 529.380 272.265 530.380 ;
        RECT 274.265 529.380 276.265 530.380 ;
        RECT 278.265 529.380 280.265 530.380 ;
        RECT 282.265 529.380 284.265 530.380 ;
        RECT 286.265 529.380 288.265 530.380 ;
        RECT 251.265 526.390 253.265 527.390 ;
        RECT 256.265 527.385 258.265 528.385 ;
        RECT 261.265 528.380 263.265 529.380 ;
        RECT 265.265 528.380 267.265 529.380 ;
        RECT 269.265 528.380 271.265 529.380 ;
        RECT 273.265 528.380 275.265 529.380 ;
        RECT 277.265 528.380 279.265 529.380 ;
        RECT 281.265 528.380 283.265 529.380 ;
        RECT 285.265 528.380 287.265 529.380 ;
        RECT 250.265 525.390 252.265 526.390 ;
        RECT 255.265 526.385 257.265 527.385 ;
        RECT 260.265 527.380 262.265 528.380 ;
        RECT 264.265 527.380 266.265 528.380 ;
        RECT 268.265 527.380 270.265 528.380 ;
        RECT 272.265 527.380 274.265 528.380 ;
        RECT 276.265 527.380 278.265 528.380 ;
        RECT 280.265 527.380 282.265 528.380 ;
        RECT 284.265 527.380 286.265 528.380 ;
        RECT 249.265 524.390 251.265 525.390 ;
        RECT 254.265 525.385 256.265 526.385 ;
        RECT 259.265 526.380 261.265 527.380 ;
        RECT 263.265 526.380 265.265 527.380 ;
        RECT 267.265 526.380 269.265 527.380 ;
        RECT 271.265 526.380 273.265 527.380 ;
        RECT 275.265 526.380 277.265 527.380 ;
        RECT 279.265 526.380 281.265 527.380 ;
        RECT 283.265 526.380 285.265 527.380 ;
        RECT 248.265 523.390 250.265 524.390 ;
        RECT 253.265 524.385 255.265 525.385 ;
        RECT 258.265 525.380 260.265 526.380 ;
        RECT 262.265 525.380 264.265 526.380 ;
        RECT 266.265 525.380 268.265 526.380 ;
        RECT 270.265 525.380 272.265 526.380 ;
        RECT 274.265 525.380 276.265 526.380 ;
        RECT 278.265 525.380 280.265 526.380 ;
        RECT 282.265 525.380 284.265 526.380 ;
        RECT 247.265 522.390 249.265 523.390 ;
        RECT 252.265 523.385 254.265 524.385 ;
        RECT 257.265 524.380 259.265 525.380 ;
        RECT 261.265 524.380 263.265 525.380 ;
        RECT 265.265 524.380 267.265 525.380 ;
        RECT 269.265 524.380 271.265 525.380 ;
        RECT 273.265 524.380 275.265 525.380 ;
        RECT 277.265 524.380 279.265 525.380 ;
        RECT 281.265 524.380 283.265 525.380 ;
        RECT 246.265 521.390 248.265 522.390 ;
        RECT 251.265 522.385 253.265 523.385 ;
        RECT 256.265 523.380 258.265 524.380 ;
        RECT 260.265 523.380 262.265 524.380 ;
        RECT 264.265 523.380 266.265 524.380 ;
        RECT 268.265 523.380 270.265 524.380 ;
        RECT 272.265 523.380 274.265 524.380 ;
        RECT 276.265 523.380 278.265 524.380 ;
        RECT 280.265 523.380 282.265 524.380 ;
        RECT 245.265 520.390 247.265 521.390 ;
        RECT 250.265 521.385 252.265 522.385 ;
        RECT 255.265 522.380 257.265 523.380 ;
        RECT 259.265 522.380 261.265 523.380 ;
        RECT 263.265 522.380 265.265 523.380 ;
        RECT 267.265 522.380 269.265 523.380 ;
        RECT 271.265 522.380 273.265 523.380 ;
        RECT 275.265 522.380 277.265 523.380 ;
        RECT 279.265 522.380 281.265 523.380 ;
        RECT 244.265 519.390 246.265 520.390 ;
        RECT 249.265 520.385 251.265 521.385 ;
        RECT 254.265 521.380 256.265 522.380 ;
        RECT 258.265 521.380 260.265 522.380 ;
        RECT 262.265 521.380 264.265 522.380 ;
        RECT 266.265 521.380 268.265 522.380 ;
        RECT 270.265 521.380 272.265 522.380 ;
        RECT 274.265 521.380 276.265 522.380 ;
        RECT 278.265 521.380 280.265 522.380 ;
        RECT 243.265 518.390 245.265 519.390 ;
        RECT 248.265 519.385 250.265 520.385 ;
        RECT 253.265 520.380 255.265 521.380 ;
        RECT 257.265 520.380 259.265 521.380 ;
        RECT 261.265 520.380 263.265 521.380 ;
        RECT 265.265 520.380 267.265 521.380 ;
        RECT 269.265 520.380 271.265 521.380 ;
        RECT 273.265 520.380 275.265 521.380 ;
        RECT 277.265 520.380 279.265 521.380 ;
        RECT 242.265 517.390 244.265 518.390 ;
        RECT 247.265 518.385 249.265 519.385 ;
        RECT 252.265 519.380 254.265 520.380 ;
        RECT 256.265 519.380 258.265 520.380 ;
        RECT 260.265 519.380 262.265 520.380 ;
        RECT 264.265 519.380 266.265 520.380 ;
        RECT 268.265 519.380 270.265 520.380 ;
        RECT 272.265 519.380 274.265 520.380 ;
        RECT 276.265 519.380 278.265 520.380 ;
        RECT 241.265 516.390 243.265 517.390 ;
        RECT 246.265 517.385 248.265 518.385 ;
        RECT 251.265 518.380 253.265 519.380 ;
        RECT 255.265 518.380 257.265 519.380 ;
        RECT 259.265 518.380 261.265 519.380 ;
        RECT 263.265 518.380 265.265 519.380 ;
        RECT 267.265 518.380 269.265 519.380 ;
        RECT 271.265 518.380 273.265 519.380 ;
        RECT 275.265 518.380 277.265 519.380 ;
        RECT 240.265 515.390 242.265 516.390 ;
        RECT 245.265 516.385 247.265 517.385 ;
        RECT 250.265 517.380 252.265 518.380 ;
        RECT 254.265 517.380 256.265 518.380 ;
        RECT 258.265 517.380 260.265 518.380 ;
        RECT 262.265 517.380 264.265 518.380 ;
        RECT 266.265 517.380 268.265 518.380 ;
        RECT 270.265 517.380 272.265 518.380 ;
        RECT 274.265 517.380 276.265 518.380 ;
        RECT 239.265 514.390 241.265 515.390 ;
        RECT 244.265 515.385 246.265 516.385 ;
        RECT 249.265 516.380 251.265 517.380 ;
        RECT 253.265 516.380 255.265 517.380 ;
        RECT 257.265 516.380 259.265 517.380 ;
        RECT 261.265 516.380 263.265 517.380 ;
        RECT 265.265 516.380 267.265 517.380 ;
        RECT 269.265 516.380 271.265 517.380 ;
        RECT 273.265 516.380 275.265 517.380 ;
        RECT 238.265 513.390 240.265 514.390 ;
        RECT 243.265 514.385 245.265 515.385 ;
        RECT 248.265 515.380 250.265 516.380 ;
        RECT 252.265 515.380 254.265 516.380 ;
        RECT 256.265 515.380 258.265 516.380 ;
        RECT 260.265 515.380 262.265 516.380 ;
        RECT 264.265 515.380 266.265 516.380 ;
        RECT 268.265 515.380 270.265 516.380 ;
        RECT 272.265 515.380 274.265 516.380 ;
        RECT 237.265 512.390 239.265 513.390 ;
        RECT 242.265 513.385 244.265 514.385 ;
        RECT 247.265 514.380 249.265 515.380 ;
        RECT 251.265 514.380 253.265 515.380 ;
        RECT 255.265 514.380 257.265 515.380 ;
        RECT 259.265 514.380 261.265 515.380 ;
        RECT 263.265 514.380 265.265 515.380 ;
        RECT 267.265 514.380 269.265 515.380 ;
        RECT 271.265 514.380 273.265 515.380 ;
        RECT 236.265 511.390 238.265 512.390 ;
        RECT 241.265 512.385 243.265 513.385 ;
        RECT 246.265 513.380 248.265 514.380 ;
        RECT 250.265 513.380 252.265 514.380 ;
        RECT 254.265 513.380 256.265 514.380 ;
        RECT 258.265 513.380 260.265 514.380 ;
        RECT 262.265 513.380 264.265 514.380 ;
        RECT 266.265 513.380 268.265 514.380 ;
        RECT 270.265 513.380 272.265 514.380 ;
        RECT 235.265 510.390 237.265 511.390 ;
        RECT 240.265 511.385 242.265 512.385 ;
        RECT 245.265 512.380 247.265 513.380 ;
        RECT 249.265 512.380 251.265 513.380 ;
        RECT 253.265 512.380 255.265 513.380 ;
        RECT 257.265 512.380 259.265 513.380 ;
        RECT 261.265 512.380 263.265 513.380 ;
        RECT 265.265 512.380 267.265 513.380 ;
        RECT 269.265 512.380 271.265 513.380 ;
        RECT 234.265 509.390 236.265 510.390 ;
        RECT 239.265 510.385 241.265 511.385 ;
        RECT 244.265 511.380 246.265 512.380 ;
        RECT 248.265 511.380 250.265 512.380 ;
        RECT 252.265 511.380 254.265 512.380 ;
        RECT 256.265 511.380 258.265 512.380 ;
        RECT 260.265 511.380 262.265 512.380 ;
        RECT 264.265 511.380 266.265 512.380 ;
        RECT 268.265 511.380 270.265 512.380 ;
        RECT 233.265 508.390 235.265 509.390 ;
        RECT 238.265 509.385 240.265 510.385 ;
        RECT 243.265 510.380 245.265 511.380 ;
        RECT 247.265 510.380 249.265 511.380 ;
        RECT 251.265 510.380 253.265 511.380 ;
        RECT 255.265 510.380 257.265 511.380 ;
        RECT 259.265 510.380 261.265 511.380 ;
        RECT 263.265 510.380 265.265 511.380 ;
        RECT 267.265 510.380 269.265 511.380 ;
        RECT 232.265 507.390 234.265 508.390 ;
        RECT 237.265 508.385 239.265 509.385 ;
        RECT 242.265 509.380 244.265 510.380 ;
        RECT 246.265 509.380 248.265 510.380 ;
        RECT 250.265 509.380 252.265 510.380 ;
        RECT 254.265 509.380 256.265 510.380 ;
        RECT 258.265 509.380 260.265 510.380 ;
        RECT 262.265 509.380 264.265 510.380 ;
        RECT 266.265 509.380 268.265 510.380 ;
        RECT 231.265 506.390 233.265 507.390 ;
        RECT 236.265 507.385 238.265 508.385 ;
        RECT 241.265 508.380 243.265 509.380 ;
        RECT 245.265 508.380 247.265 509.380 ;
        RECT 249.265 508.380 251.265 509.380 ;
        RECT 253.265 508.380 255.265 509.380 ;
        RECT 257.265 508.380 259.265 509.380 ;
        RECT 261.265 508.380 263.265 509.380 ;
        RECT 265.265 508.380 267.265 509.380 ;
        RECT 230.265 505.390 232.265 506.390 ;
        RECT 235.265 506.385 237.265 507.385 ;
        RECT 240.265 507.380 242.265 508.380 ;
        RECT 244.265 507.380 246.265 508.380 ;
        RECT 248.265 507.380 250.265 508.380 ;
        RECT 252.265 507.380 254.265 508.380 ;
        RECT 256.265 507.380 258.265 508.380 ;
        RECT 260.265 507.380 262.265 508.380 ;
        RECT 264.265 507.380 266.265 508.380 ;
        RECT 229.265 504.390 231.265 505.390 ;
        RECT 234.265 505.385 236.265 506.385 ;
        RECT 239.265 506.380 241.265 507.380 ;
        RECT 243.265 506.380 245.265 507.380 ;
        RECT 247.265 506.380 249.265 507.380 ;
        RECT 251.265 506.380 253.265 507.380 ;
        RECT 255.265 506.380 257.265 507.380 ;
        RECT 259.265 506.380 261.265 507.380 ;
        RECT 263.265 506.380 265.265 507.380 ;
        RECT 228.265 503.390 230.265 504.390 ;
        RECT 233.265 504.385 235.265 505.385 ;
        RECT 238.265 505.380 240.265 506.380 ;
        RECT 242.265 505.380 244.265 506.380 ;
        RECT 246.265 505.380 248.265 506.380 ;
        RECT 250.265 505.380 252.265 506.380 ;
        RECT 254.265 505.380 256.265 506.380 ;
        RECT 258.265 505.380 260.265 506.380 ;
        RECT 262.265 505.380 264.265 506.380 ;
        RECT 227.265 502.390 229.265 503.390 ;
        RECT 232.265 503.385 234.265 504.385 ;
        RECT 237.265 504.380 239.265 505.380 ;
        RECT 241.265 504.380 243.265 505.380 ;
        RECT 245.265 504.380 247.265 505.380 ;
        RECT 249.265 504.380 251.265 505.380 ;
        RECT 253.265 504.380 255.265 505.380 ;
        RECT 257.265 504.380 259.265 505.380 ;
        RECT 261.265 504.380 263.265 505.380 ;
        RECT 226.265 501.390 228.265 502.390 ;
        RECT 231.265 502.385 233.265 503.385 ;
        RECT 236.265 503.380 238.265 504.380 ;
        RECT 240.265 503.380 242.265 504.380 ;
        RECT 244.265 503.380 246.265 504.380 ;
        RECT 248.265 503.380 250.265 504.380 ;
        RECT 252.265 503.380 254.265 504.380 ;
        RECT 256.265 503.380 258.265 504.380 ;
        RECT 260.265 503.380 262.265 504.380 ;
        RECT 225.265 500.390 227.265 501.390 ;
        RECT 230.265 501.385 232.265 502.385 ;
        RECT 235.265 502.380 237.265 503.380 ;
        RECT 239.265 502.380 241.265 503.380 ;
        RECT 243.265 502.380 245.265 503.380 ;
        RECT 247.265 502.380 249.265 503.380 ;
        RECT 251.265 502.380 253.265 503.380 ;
        RECT 255.265 502.380 257.265 503.380 ;
        RECT 259.265 502.380 261.265 503.380 ;
        RECT 224.265 499.390 226.265 500.390 ;
        RECT 229.265 500.385 231.265 501.385 ;
        RECT 234.265 501.380 236.265 502.380 ;
        RECT 238.265 501.380 240.265 502.380 ;
        RECT 242.265 501.380 244.265 502.380 ;
        RECT 246.265 501.380 248.265 502.380 ;
        RECT 250.265 501.380 252.265 502.380 ;
        RECT 254.265 501.380 256.265 502.380 ;
        RECT 258.265 501.380 260.265 502.380 ;
        RECT 223.265 498.390 225.265 499.390 ;
        RECT 228.265 499.385 230.265 500.385 ;
        RECT 233.265 500.380 235.265 501.380 ;
        RECT 237.265 500.380 239.265 501.380 ;
        RECT 241.265 500.380 243.265 501.380 ;
        RECT 245.265 500.380 247.265 501.380 ;
        RECT 249.265 500.380 251.265 501.380 ;
        RECT 253.265 500.380 255.265 501.380 ;
        RECT 257.265 500.380 259.265 501.380 ;
        RECT 222.265 497.390 224.265 498.390 ;
        RECT 227.265 498.385 229.265 499.385 ;
        RECT 232.265 499.380 234.265 500.380 ;
        RECT 236.265 499.380 238.265 500.380 ;
        RECT 240.265 499.380 242.265 500.380 ;
        RECT 244.265 499.380 246.265 500.380 ;
        RECT 248.265 499.380 250.265 500.380 ;
        RECT 252.265 499.380 254.265 500.380 ;
        RECT 256.265 499.380 258.265 500.380 ;
        RECT 221.265 496.390 223.265 497.390 ;
        RECT 226.265 497.385 228.265 498.385 ;
        RECT 231.265 498.380 233.265 499.380 ;
        RECT 235.265 498.380 237.265 499.380 ;
        RECT 239.265 498.380 241.265 499.380 ;
        RECT 243.265 498.380 245.265 499.380 ;
        RECT 247.265 498.380 249.265 499.380 ;
        RECT 251.265 498.380 253.265 499.380 ;
        RECT 255.265 498.380 257.265 499.380 ;
        RECT 220.265 495.390 222.265 496.390 ;
        RECT 225.265 496.385 227.265 497.385 ;
        RECT 230.265 497.380 232.265 498.380 ;
        RECT 234.265 497.380 236.265 498.380 ;
        RECT 238.265 497.380 240.265 498.380 ;
        RECT 242.265 497.380 244.265 498.380 ;
        RECT 246.265 497.380 248.265 498.380 ;
        RECT 250.265 497.380 252.265 498.380 ;
        RECT 254.265 497.380 256.265 498.380 ;
        RECT 219.265 494.390 221.265 495.390 ;
        RECT 224.265 495.385 226.265 496.385 ;
        RECT 229.265 496.380 231.265 497.380 ;
        RECT 233.265 496.380 235.265 497.380 ;
        RECT 237.265 496.380 239.265 497.380 ;
        RECT 241.265 496.380 243.265 497.380 ;
        RECT 245.265 496.380 247.265 497.380 ;
        RECT 249.265 496.380 251.265 497.380 ;
        RECT 253.265 496.380 255.265 497.380 ;
        RECT 218.265 493.390 220.265 494.390 ;
        RECT 223.265 494.385 225.265 495.385 ;
        RECT 228.265 495.380 230.265 496.380 ;
        RECT 232.265 495.380 234.265 496.380 ;
        RECT 236.265 495.380 238.265 496.380 ;
        RECT 240.265 495.380 242.265 496.380 ;
        RECT 244.265 495.380 246.265 496.380 ;
        RECT 248.265 495.380 250.265 496.380 ;
        RECT 252.265 495.380 254.265 496.380 ;
        RECT 217.265 492.390 219.265 493.390 ;
        RECT 222.265 493.385 224.265 494.385 ;
        RECT 227.265 494.380 229.265 495.380 ;
        RECT 231.265 494.380 233.265 495.380 ;
        RECT 235.265 494.380 237.265 495.380 ;
        RECT 239.265 494.380 241.265 495.380 ;
        RECT 243.265 494.380 245.265 495.380 ;
        RECT 247.265 494.380 249.265 495.380 ;
        RECT 251.265 494.380 253.265 495.380 ;
        RECT 216.265 491.390 218.265 492.390 ;
        RECT 221.265 492.385 223.265 493.385 ;
        RECT 226.265 493.380 228.265 494.380 ;
        RECT 230.265 493.380 232.265 494.380 ;
        RECT 234.265 493.380 236.265 494.380 ;
        RECT 238.265 493.380 240.265 494.380 ;
        RECT 242.265 493.380 244.265 494.380 ;
        RECT 246.265 493.380 248.265 494.380 ;
        RECT 250.265 493.380 252.265 494.380 ;
        RECT 216.265 490.390 217.265 491.390 ;
        RECT 220.265 491.385 222.265 492.385 ;
        RECT 225.265 492.380 227.265 493.380 ;
        RECT 229.265 492.380 231.265 493.380 ;
        RECT 233.265 492.380 235.265 493.380 ;
        RECT 237.265 492.380 239.265 493.380 ;
        RECT 241.265 492.380 243.265 493.380 ;
        RECT 245.265 492.380 247.265 493.380 ;
        RECT 249.265 492.380 251.265 493.380 ;
        RECT 220.265 490.385 221.265 491.385 ;
        RECT 224.265 491.380 226.265 492.380 ;
        RECT 228.265 491.380 230.265 492.380 ;
        RECT 232.265 491.380 234.265 492.380 ;
        RECT 236.265 491.380 238.265 492.380 ;
        RECT 240.265 491.380 242.265 492.380 ;
        RECT 244.265 491.380 246.265 492.380 ;
        RECT 248.265 491.380 250.265 492.380 ;
        RECT 224.265 490.380 225.265 491.380 ;
        RECT 228.265 490.380 229.265 491.380 ;
        RECT 232.265 490.380 233.265 491.380 ;
        RECT 236.265 490.380 237.265 491.380 ;
        RECT 240.265 490.380 241.265 491.380 ;
        RECT 244.265 490.380 245.265 491.380 ;
        RECT 248.265 490.380 249.265 491.380 ;
        RECT 410.200 476.265 413.200 596.265 ;
        RECT 414.100 476.265 417.100 596.265 ;
        RECT 418.000 476.265 421.000 596.265 ;
        RECT 421.910 476.265 424.910 596.265 ;
        RECT 425.820 476.265 428.820 596.265 ;
        RECT 429.740 476.265 432.740 596.265 ;
        RECT 433.660 476.265 436.660 596.265 ;
        RECT 437.590 476.265 440.590 596.265 ;
        RECT 441.520 476.265 444.520 596.265 ;
        RECT 445.460 476.265 448.460 596.265 ;
        RECT 449.400 476.265 452.400 596.265 ;
        RECT 453.350 476.265 456.350 596.265 ;
        RECT 457.300 476.265 460.300 596.265 ;
        RECT 461.260 476.265 464.260 596.265 ;
        RECT 465.220 476.265 468.220 596.265 ;
        RECT 469.190 476.265 472.190 596.265 ;
        RECT 473.160 476.265 476.160 596.265 ;
        RECT 477.140 476.265 480.140 596.265 ;
        RECT 481.120 476.265 484.120 596.265 ;
        RECT 485.110 476.265 488.110 596.265 ;
        RECT 489.100 476.265 492.100 596.265 ;
        RECT 493.100 476.265 496.100 596.265 ;
        RECT 497.100 476.265 500.100 596.265 ;
        RECT 501.110 476.265 504.110 596.265 ;
        RECT 505.120 476.265 508.120 596.265 ;
        RECT 509.140 476.265 512.140 596.265 ;
        RECT 513.160 476.265 516.160 596.265 ;
        RECT 517.190 476.265 520.190 596.265 ;
        RECT 521.220 476.265 524.220 596.265 ;
        RECT 525.260 476.265 528.260 596.265 ;
        RECT 529.300 476.265 532.300 596.265 ;
        RECT 533.350 476.265 536.350 596.265 ;
        RECT 537.400 476.265 540.400 596.265 ;
        RECT 541.460 476.265 544.460 596.265 ;
        RECT 545.520 476.265 548.520 596.265 ;
        RECT 549.590 476.265 552.590 596.265 ;
        RECT 553.660 476.265 556.660 596.265 ;
        RECT 557.740 476.265 560.740 596.265 ;
        RECT 561.820 476.265 564.820 596.265 ;
        RECT 565.910 476.265 568.910 596.265 ;
        RECT 570.000 476.265 573.000 596.265 ;
        RECT 574.100 476.265 577.100 596.265 ;
        RECT 578.200 476.265 581.200 596.265 ;
        RECT 582.310 476.265 585.310 596.265 ;
        RECT 586.420 476.265 589.420 596.265 ;
        RECT 590.540 476.265 593.540 596.265 ;
        RECT 594.660 476.265 597.660 596.265 ;
        RECT 598.790 476.265 601.790 596.265 ;
        RECT 602.920 476.265 605.920 596.265 ;
        RECT 607.060 476.265 610.060 596.265 ;
        RECT 611.200 476.265 614.200 596.265 ;
        RECT 615.350 476.265 618.350 596.265 ;
        RECT 619.500 476.265 622.500 596.265 ;
        RECT 623.660 476.265 626.660 596.265 ;
        RECT 627.820 476.265 630.820 596.265 ;
        RECT 631.990 476.265 634.990 596.265 ;
        RECT 636.160 476.265 639.160 596.265 ;
        RECT 640.340 476.265 643.340 596.265 ;
        RECT 644.520 476.265 647.520 596.265 ;
        RECT 648.710 476.265 651.710 596.265 ;
        RECT 652.900 476.265 655.900 596.265 ;
        RECT 657.100 476.265 660.100 596.265 ;
        RECT 661.300 476.265 664.300 596.265 ;
        RECT 665.510 476.265 668.510 596.265 ;
        RECT 669.720 476.265 672.720 596.265 ;
        RECT 673.940 476.265 676.940 596.265 ;
        RECT 678.160 476.265 681.160 596.265 ;
        RECT 682.390 476.265 685.390 596.265 ;
        RECT 686.620 476.265 689.620 596.265 ;
        RECT 690.860 476.265 693.860 596.265 ;
        RECT 695.100 476.265 698.100 596.265 ;
        RECT 699.350 476.265 702.350 596.265 ;
        RECT 703.600 476.265 706.600 596.265 ;
        RECT 707.860 476.265 710.860 596.265 ;
        RECT 712.120 476.265 715.120 596.265 ;
        RECT 716.390 476.265 719.390 596.265 ;
        RECT 720.660 476.265 723.660 596.265 ;
        RECT 724.940 476.265 727.940 596.265 ;
        RECT 729.220 476.265 732.220 596.265 ;
        RECT 733.510 476.265 736.510 596.265 ;
        RECT 737.800 476.265 740.800 596.265 ;
        RECT 742.100 476.265 745.100 596.265 ;
        RECT 746.400 476.265 749.400 596.265 ;
        RECT 750.710 476.265 753.710 596.265 ;
        RECT 755.020 476.265 758.020 596.265 ;
        RECT 759.340 476.265 762.340 596.265 ;
        RECT 763.660 476.265 766.660 596.265 ;
        RECT 767.990 476.265 770.990 596.265 ;
        RECT 772.320 476.265 775.320 596.265 ;
        RECT 776.660 476.265 779.660 596.265 ;
        RECT 781.000 476.265 784.000 596.265 ;
        RECT 785.350 476.265 788.350 596.265 ;
        RECT 789.700 476.265 792.700 596.265 ;
        RECT 794.060 476.265 797.060 596.265 ;
        RECT 798.420 476.265 801.420 596.265 ;
        RECT 802.790 476.265 805.790 596.265 ;
        RECT 807.160 476.265 810.160 596.265 ;
        RECT 811.540 476.265 814.540 596.265 ;
        RECT 815.920 476.265 818.920 596.265 ;
        RECT 820.310 476.265 823.310 596.265 ;
        RECT 824.700 476.265 827.700 596.265 ;
        RECT 829.100 476.265 832.100 596.265 ;
        RECT 833.500 476.265 836.500 596.265 ;
        RECT 837.910 476.265 840.910 596.265 ;
        RECT 842.320 476.265 845.320 596.265 ;
        RECT 846.740 476.265 849.740 596.265 ;
        RECT 851.160 476.265 854.160 596.265 ;
        RECT 855.590 476.265 858.590 596.265 ;
        RECT 860.020 476.265 863.020 596.265 ;
        RECT 864.460 476.265 867.460 596.265 ;
        RECT 868.900 476.265 871.900 596.265 ;
        RECT 873.350 476.265 876.350 596.265 ;
        RECT 877.800 476.265 880.800 596.265 ;
        RECT 882.260 476.265 885.260 596.265 ;
        RECT 886.720 476.265 889.720 596.265 ;
        RECT 891.190 476.265 894.190 596.265 ;
        RECT 895.660 476.265 898.660 596.265 ;
        RECT 900.140 476.265 903.140 596.265 ;
        RECT 904.620 476.265 907.620 596.265 ;
        RECT 909.110 476.265 912.110 596.265 ;
        RECT 913.600 476.265 916.600 596.265 ;
        RECT 918.100 476.265 921.100 596.265 ;
        RECT 922.600 476.265 925.600 596.265 ;
        RECT 7.000 306.000 8.000 456.000 ;
        RECT 8.460 306.000 9.460 456.000 ;
        RECT 9.920 306.000 10.920 456.000 ;
        RECT 11.380 306.000 12.380 456.000 ;
        RECT 12.840 306.000 13.840 456.000 ;
        RECT 14.300 306.000 15.300 456.000 ;
        RECT 15.760 306.000 16.760 456.000 ;
        RECT 17.220 306.000 18.220 456.000 ;
        RECT 18.680 306.000 19.680 456.000 ;
        RECT 20.140 306.000 21.140 456.000 ;
        RECT 21.600 306.000 22.600 456.000 ;
        RECT 23.060 306.000 24.060 456.000 ;
        RECT 24.520 306.000 25.520 456.000 ;
        RECT 25.980 306.000 26.980 456.000 ;
        RECT 27.440 306.000 28.440 456.000 ;
        RECT 28.900 306.000 29.900 456.000 ;
        RECT 30.360 306.000 31.360 456.000 ;
        RECT 31.820 306.000 32.820 456.000 ;
        RECT 33.280 306.000 34.280 456.000 ;
        RECT 34.740 306.000 35.740 456.000 ;
        RECT 36.200 306.000 37.200 456.000 ;
        RECT 37.660 306.000 38.660 456.000 ;
        RECT 39.120 306.000 40.120 456.000 ;
        RECT 40.580 306.000 41.580 456.000 ;
        RECT 42.040 306.000 43.040 456.000 ;
        RECT 43.500 306.000 44.500 456.000 ;
        RECT 44.960 306.000 45.960 456.000 ;
        RECT 46.420 306.000 47.420 456.000 ;
        RECT 47.880 306.000 48.880 456.000 ;
        RECT 49.340 306.000 50.340 456.000 ;
        RECT 50.800 306.000 51.800 456.000 ;
        RECT 52.260 306.000 53.260 456.000 ;
        RECT 53.730 306.000 54.730 456.000 ;
        RECT 55.200 306.000 56.200 456.000 ;
        RECT 56.670 306.000 57.670 456.000 ;
        RECT 58.140 306.000 59.140 456.000 ;
        RECT 59.620 306.000 60.620 456.000 ;
        RECT 61.100 306.000 62.100 456.000 ;
        RECT 62.580 306.000 63.580 456.000 ;
        RECT 64.060 306.000 65.060 456.000 ;
        RECT 65.550 306.000 66.550 456.000 ;
        RECT 67.040 306.000 68.040 456.000 ;
        RECT 68.530 306.000 69.530 456.000 ;
        RECT 70.020 306.000 71.020 456.000 ;
        RECT 71.520 306.000 72.520 456.000 ;
        RECT 73.020 306.000 74.020 456.000 ;
        RECT 74.520 306.000 75.520 456.000 ;
        RECT 76.020 306.000 77.020 456.000 ;
        RECT 77.530 306.000 78.530 456.000 ;
        RECT 79.040 306.000 80.040 456.000 ;
        RECT 80.550 306.000 81.550 456.000 ;
        RECT 82.060 306.000 83.060 456.000 ;
        RECT 83.580 306.000 84.580 456.000 ;
        RECT 85.100 306.000 86.100 456.000 ;
        RECT 86.620 306.000 87.620 456.000 ;
        RECT 88.140 306.000 89.140 456.000 ;
        RECT 89.670 306.000 90.670 456.000 ;
        RECT 91.200 306.000 92.200 456.000 ;
        RECT 92.730 306.000 93.730 456.000 ;
        RECT 94.260 306.000 95.260 456.000 ;
        RECT 95.800 306.000 96.800 456.000 ;
        RECT 97.340 306.000 98.340 456.000 ;
        RECT 98.880 306.000 99.880 456.000 ;
        RECT 100.420 306.000 101.420 456.000 ;
        RECT 101.970 306.000 102.970 456.000 ;
        RECT 103.520 306.000 104.520 456.000 ;
        RECT 105.070 306.000 106.070 456.000 ;
        RECT 106.620 306.000 107.620 456.000 ;
        RECT 108.180 306.000 109.180 456.000 ;
        RECT 109.740 306.000 110.740 456.000 ;
        RECT 111.300 306.000 112.300 456.000 ;
        RECT 112.860 306.000 113.860 456.000 ;
        RECT 114.430 306.000 115.430 456.000 ;
        RECT 116.000 306.000 117.000 456.000 ;
        RECT 117.570 306.000 118.570 456.000 ;
        RECT 119.140 306.000 120.140 456.000 ;
        RECT 120.720 306.000 121.720 456.000 ;
        RECT 122.300 306.000 123.300 456.000 ;
        RECT 123.880 306.000 124.880 456.000 ;
        RECT 125.460 306.000 126.460 456.000 ;
        RECT 127.050 306.000 128.050 456.000 ;
        RECT 128.640 306.000 129.640 456.000 ;
        RECT 130.230 306.000 131.230 456.000 ;
        RECT 131.820 306.000 132.820 456.000 ;
        RECT 133.420 306.000 134.420 456.000 ;
        RECT 135.020 306.000 136.020 456.000 ;
        RECT 136.620 306.000 137.620 456.000 ;
        RECT 138.220 306.000 139.220 456.000 ;
        RECT 139.830 306.000 140.830 456.000 ;
        RECT 141.440 306.000 142.440 456.000 ;
        RECT 143.050 306.000 144.050 456.000 ;
        RECT 144.660 306.000 145.660 456.000 ;
        RECT 146.280 306.000 147.280 456.000 ;
        RECT 147.900 306.000 148.900 456.000 ;
        RECT 149.520 306.000 150.520 456.000 ;
        RECT 151.140 306.000 152.140 456.000 ;
        RECT 152.770 306.000 153.770 456.000 ;
        RECT 154.400 306.000 155.400 456.000 ;
        RECT 156.030 306.000 157.030 456.000 ;
        RECT 157.660 306.000 158.660 456.000 ;
        RECT 159.300 306.000 160.300 456.000 ;
        RECT 160.940 306.000 161.940 456.000 ;
        RECT 162.580 306.000 163.580 456.000 ;
        RECT 164.220 306.000 165.220 456.000 ;
        RECT 165.870 306.000 166.870 456.000 ;
        RECT 167.520 306.000 168.520 456.000 ;
        RECT 169.170 306.000 170.170 456.000 ;
        RECT 170.820 306.000 171.820 456.000 ;
        RECT 172.480 306.000 173.480 456.000 ;
        RECT 174.140 306.000 175.140 456.000 ;
        RECT 175.800 306.000 176.800 456.000 ;
        RECT 177.460 306.000 178.460 456.000 ;
        RECT 179.130 306.000 180.130 456.000 ;
        RECT 180.800 306.000 181.800 456.000 ;
        RECT 182.470 306.000 183.470 456.000 ;
        RECT 184.140 306.000 185.140 456.000 ;
        RECT 185.820 306.000 186.820 456.000 ;
        RECT 187.500 306.000 188.500 456.000 ;
        RECT 189.180 306.000 190.180 456.000 ;
        RECT 190.860 306.000 191.860 456.000 ;
        RECT 192.550 306.000 193.550 456.000 ;
        RECT 194.240 306.000 195.240 456.000 ;
        RECT 195.930 306.000 196.930 456.000 ;
        RECT 197.620 306.000 198.620 456.000 ;
        RECT 199.320 306.000 200.320 456.000 ;
        RECT 201.020 306.000 202.020 456.000 ;
        RECT 202.720 306.000 203.720 456.000 ;
        RECT 204.420 306.000 205.420 456.000 ;
        RECT 509.700 306.000 519.700 456.000 ;
        RECT 520.700 306.000 530.700 456.000 ;
        RECT 531.700 306.000 541.700 456.000 ;
        RECT 542.700 306.000 552.700 456.000 ;
        RECT 553.700 306.000 563.700 456.000 ;
        RECT 564.700 306.000 574.700 456.000 ;
        RECT 575.700 306.000 585.700 456.000 ;
        RECT 586.700 306.000 596.700 456.000 ;
        RECT 597.700 306.000 607.700 456.000 ;
        RECT 608.700 306.000 618.700 456.000 ;
        RECT 620.700 306.000 630.700 456.000 ;
        RECT 632.700 306.000 642.700 456.000 ;
        RECT 644.700 306.000 654.700 456.000 ;
        RECT 656.700 306.000 666.700 456.000 ;
        RECT 668.700 306.000 678.700 456.000 ;
        RECT 680.700 306.000 690.700 456.000 ;
        RECT 694.700 306.000 704.700 456.000 ;
        RECT 708.700 306.000 718.700 456.000 ;
        RECT 722.700 306.000 732.700 456.000 ;
        RECT 736.700 306.000 746.700 456.000 ;
        RECT 750.700 306.000 760.700 456.000 ;
        RECT 764.700 306.000 774.700 456.000 ;
        RECT 778.700 306.000 788.700 456.000 ;
        RECT 405.740 247.150 406.180 298.415 ;
        RECT 407.780 247.150 408.230 298.415 ;
        RECT 409.830 247.150 410.290 298.415 ;
        RECT 411.890 247.150 412.360 298.415 ;
        RECT 413.960 247.150 414.440 298.415 ;
        RECT 416.040 247.150 416.530 298.415 ;
        RECT 418.130 247.150 418.630 298.415 ;
        RECT 420.230 247.150 420.740 298.415 ;
        RECT 422.340 247.150 422.860 298.415 ;
        RECT 424.460 247.150 424.990 298.415 ;
        RECT 426.590 247.150 427.130 298.415 ;
        RECT 428.730 247.150 429.280 298.415 ;
        RECT 430.880 247.150 431.440 298.415 ;
        RECT 433.040 247.150 433.610 298.415 ;
        RECT 435.210 247.150 435.790 298.415 ;
        RECT 437.390 247.150 437.980 298.415 ;
        RECT 439.580 247.150 440.180 298.415 ;
        RECT 441.780 247.150 442.390 298.415 ;
        RECT 443.990 247.150 444.610 298.415 ;
        RECT 446.210 247.150 446.840 298.415 ;
        RECT 448.440 247.150 449.080 298.415 ;
        RECT 450.680 247.150 451.330 298.415 ;
        RECT 452.930 247.150 453.590 298.415 ;
        RECT 455.190 247.150 455.860 298.415 ;
        RECT 457.460 247.150 458.140 298.415 ;
        RECT 459.740 247.150 460.430 298.415 ;
        RECT 462.030 247.150 462.730 298.415 ;
        RECT 464.730 247.150 465.440 298.415 ;
        RECT 467.440 247.150 468.160 298.415 ;
        RECT 470.160 247.150 470.890 298.415 ;
        RECT 472.890 247.150 473.630 298.415 ;
        RECT 475.630 247.150 476.380 298.415 ;
        RECT 478.380 247.150 479.140 298.415 ;
        RECT 481.140 247.150 481.910 298.415 ;
        RECT 483.910 247.150 484.690 298.415 ;
        RECT 486.690 247.150 487.480 298.415 ;
        RECT 489.480 247.150 490.280 298.415 ;
        RECT 492.280 247.150 493.090 298.415 ;
        RECT 495.090 247.150 495.910 298.415 ;
        RECT 497.910 247.150 498.740 298.415 ;
        RECT 500.740 247.150 501.580 298.415 ;
        RECT 503.580 247.150 504.430 298.415 ;
        RECT 506.430 247.150 507.290 298.415 ;
        RECT 509.290 247.150 510.160 298.415 ;
        RECT 512.160 247.150 513.040 298.415 ;
        RECT 515.040 247.150 515.930 298.415 ;
        RECT 517.930 247.150 518.830 298.415 ;
        RECT 520.830 247.150 521.740 298.415 ;
        RECT 523.740 247.150 524.660 298.415 ;
        RECT 526.660 247.150 527.590 298.415 ;
        RECT 529.590 247.150 530.530 298.415 ;
        RECT 532.530 247.150 533.480 298.415 ;
        RECT 535.480 247.150 536.440 298.415 ;
        RECT 538.440 247.150 539.410 298.415 ;
        RECT 541.410 247.150 542.390 298.415 ;
        RECT 544.390 247.150 545.380 298.415 ;
        RECT 547.380 247.150 548.380 298.415 ;
        RECT 550.380 247.150 551.390 298.415 ;
        RECT 553.390 247.150 554.410 298.415 ;
        RECT 556.410 247.150 557.440 298.415 ;
        RECT 559.440 247.150 560.480 298.415 ;
        RECT 562.480 247.150 563.530 298.415 ;
        RECT 565.530 247.150 566.590 298.415 ;
        RECT 568.590 247.150 569.660 298.415 ;
        RECT 571.660 247.150 572.740 298.415 ;
        RECT 574.740 247.150 575.830 298.415 ;
        RECT 577.830 247.150 578.930 298.415 ;
        RECT 580.930 247.150 582.040 298.415 ;
        RECT 584.040 247.150 585.160 298.415 ;
        RECT 587.160 247.150 588.290 298.415 ;
        RECT 590.290 247.150 591.430 298.415 ;
        RECT 593.430 247.150 594.580 298.415 ;
        RECT 596.580 247.150 597.740 298.415 ;
        RECT 599.740 247.150 600.910 298.415 ;
        RECT 602.910 247.150 604.090 298.415 ;
        RECT 606.090 247.150 607.280 298.415 ;
        RECT 609.280 247.150 610.480 298.415 ;
        RECT 612.480 247.150 613.690 298.415 ;
        RECT 615.690 247.150 616.910 298.415 ;
        RECT 618.910 247.150 620.140 298.415 ;
        RECT 622.140 247.150 623.380 298.415 ;
        RECT 625.380 247.150 626.630 298.415 ;
        RECT 628.630 247.150 629.890 298.415 ;
        RECT 631.890 247.150 633.160 298.415 ;
        RECT 635.160 247.150 636.440 298.415 ;
        RECT 638.440 247.150 639.730 298.415 ;
        RECT 641.730 247.150 643.030 298.415 ;
        RECT 645.030 247.150 646.340 298.415 ;
        RECT 648.340 247.150 649.660 298.415 ;
        RECT 651.660 247.150 652.990 298.415 ;
        RECT 654.990 247.150 656.330 298.415 ;
        RECT 658.330 247.150 659.680 298.415 ;
        RECT 661.680 247.150 663.040 298.415 ;
        RECT 665.040 247.150 666.410 298.415 ;
        RECT 668.410 247.150 669.790 298.415 ;
        RECT 671.790 247.150 673.180 298.415 ;
        RECT 675.180 247.150 676.580 298.415 ;
        RECT 678.580 247.150 679.990 298.415 ;
        RECT 327.055 186.050 356.960 215.960 ;
        RECT 7.000 116.000 37.000 146.000 ;
        RECT 47.000 116.000 77.000 146.000 ;
        RECT 7.000 46.000 37.000 76.000 ;
        RECT 47.000 46.000 77.000 76.000 ;
        RECT 7.000 6.000 37.000 36.000 ;
        RECT 47.000 6.000 77.000 36.000 ;
        RECT 928.680 6.000 929.130 605.275 ;
        RECT 1.870 0.785 934.970 1.795 ;
  END
END palette_1
END LIBRARY

